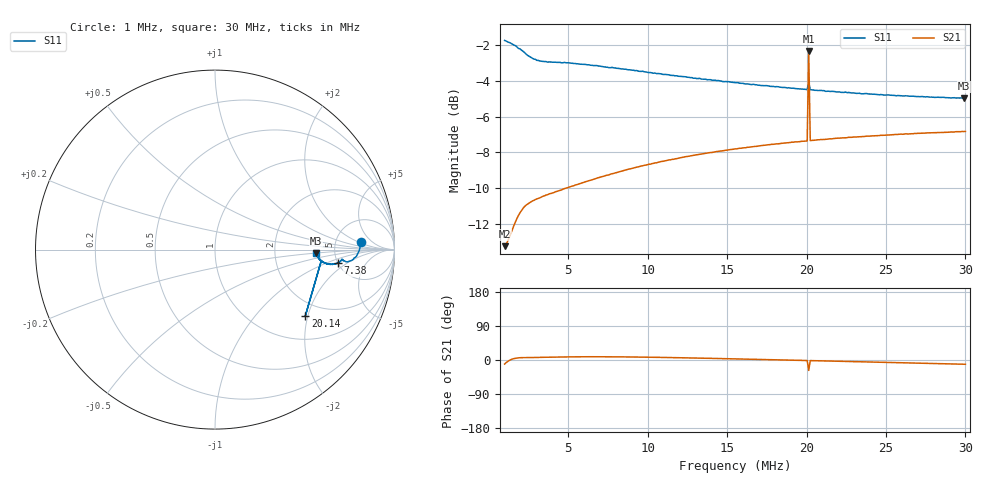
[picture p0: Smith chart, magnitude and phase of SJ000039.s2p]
!File created by NanoVNA-F V2
# Hz S RI R 50
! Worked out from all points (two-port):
!   301 points, 1 MHz to 30 MHz, reference 50 ohm
!   highest |S21| = -2.35 dB at 20.14 MHz (marker M1); lowest = -13.2 dB at 1 MHz (marker M2)
!   |S21| within 3 dB of the highest: 20.08 MHz to 20.2 MHz (116 kHz wide, 0.576 % of centre)
!   lowest |S11| = -5.0 dB at 29.9 MHz (marker M3), VSWR 3.58, Z = 179 - j9.52 ohm
!   |S11| at or under -10 dB: nowhere
!   S12 and S22 are empty: the file has one direction only
!   S11 on the Smith chart (normalised r, x): 1 MHz: 9.30, +2.28; 7.38 MHz: 5.00, -1.43; 20.14 MHz: 1.59, -1.93; 30 MHz: 3.58, -0.20
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1000000  0.815 0.041  0.2146 -0.0406  0 0  0 0
1289998  0.8055 0.000866  0.2307 -0.00534  0 0  0 0
1579996  0.792 -0.0278  0.2485 0.0158  0 0  0 0
1966660  0.7713 -0.0535  0.2689 0.0282  0 0  0 0
2449990  0.7385 -0.0681  0.2844 0.0317  0 0  0 0
2836654  0.7214 -0.0636  0.2909 0.0334  0 0  0 0
3223318  0.7125 -0.0603  0.2956 0.0355  0 0  0 0
3706648  0.7082 -0.0545  0.3012 0.0382  0 0  0 0
4479976  0.7071 -0.055  0.3095 0.0424  0 0  0 0
5833300  0.6976 -0.0656  0.3236 0.0478  0 0  0 0
7379956  0.6844 -0.0752  0.3398 0.0505  0 0  0 0
1.06666e7  0.6551 -0.0817  0.3711 0.0453  0 0  0 0
1.240659e7  0.641 -0.0831  0.3857 0.038  0 0  0 0
1.54999e7  0.6183 -0.0762  0.4067 0.0211  0 0  0 0
2.00432e7  0.5922 -0.0626  0.4283 -0.0104  0 0  0 0
2.013987e7  0.503 -0.3702  0.677 -0.3516  0 0  0 0
2.023653e7  0.5921 -0.0618  0.4293 -0.0117  0 0  0 0
2.03332e7  0.5913 -0.0618  0.4299 -0.0128  0 0  0 0
2.168652e7  0.5855 -0.0588  0.4345 -0.0229  0 0  0 0
2.51665e7  0.5741 -0.0409  0.4422 -0.0503  0 0  0 0
2.990313e7  0.5633 -0.0182  0.4467 -0.0878  0 0  0 0
2.99998e7  0.5638 -0.0193  0.4469 -0.0888  0 0  0 0
